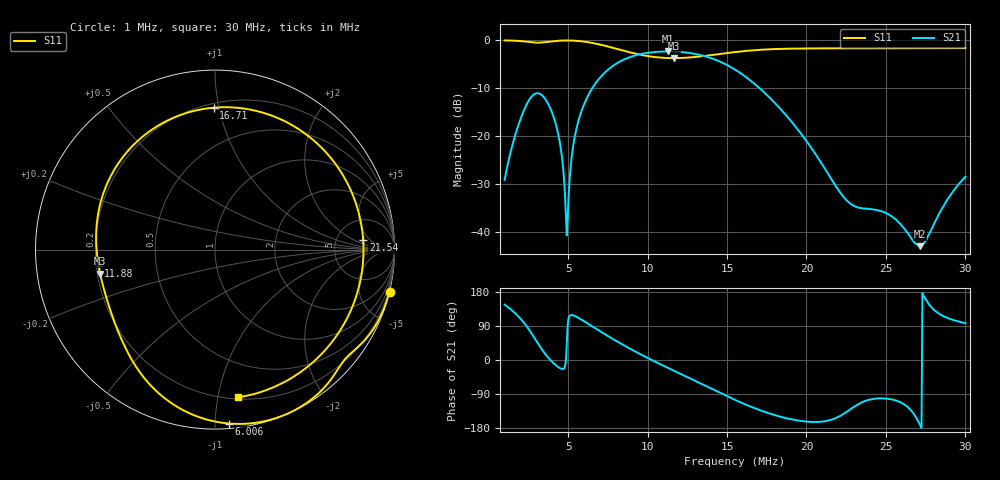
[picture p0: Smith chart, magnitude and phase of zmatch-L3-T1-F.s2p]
# HZ S RI R 50
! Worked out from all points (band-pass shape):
!   505 points, 1 MHz to 30 MHz, reference 50 ohm
!   highest |S21| = -2.30 dB at 11.3 MHz (marker M1); lowest = -43.0 dB at 27.12 MHz (marker M2)
!   |S21| within 3 dB of the highest: 7.824 MHz to 15.09 MHz (7.266 MHz wide, 63.4 % of centre)
!   lowest |S11| = -3.7 dB at 11.64 MHz (marker M3), VSWR 4.78, Z = 10.6 - j4.93 ohm
!   |S11| at or under -10 dB: nowhere
!   S12 and S22 are empty: the file has one direction only
!   S11 on the Smith chart (normalised r, x): 1 MHz: 0.00, -8.44; 6.006 MHz: 0.03, -1.08; 11.88 MHz: 0.21, -0.07; 16.71 MHz: 0.23, +0.96; 21.54 MHz: 10, +3; 30 MHz: 0.21, -1.15
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1000000  0.9723 -0.2336  -0.029 0.0195  0 0  0 0
2208340  0.8432 -0.4945  -0.0283 0.183  0 0  0 0
3244060  0.7047 -0.6362  0.2277 0.1555  0 0  0 0
4337320  0.5416 -0.831  0.1065 -0.0341  0 0  0 0
4912720  0.3995 -0.9166  0.00688 0.00614  0 0  0 0
5315500  0.2844 -0.9542  -0.0369 0.0697  0 0  0 0
5833360  0.1285 -0.9713  -0.0516 0.1745  0 0  0 0
6005980  0.0765 -0.9691  -0.0451 0.2117  0 0  0 0
8134960  -0.4049 -0.7019  0.3964 0.4322  0 0  0 0
1.066672e7  -0.5984 -0.2902  0.7537 -0.1124  0 0  0 0
1.129966e7  -0.6268 -0.1908  0.7153 -0.2783  0 0  0 0
1.16449e7  -0.6401 -0.1335  0.675 -0.3612  0 0  0 0
1.187506e7  -0.6477 -0.0935  0.6411 -0.4122  0 0  0 0
1.36588e7  -0.6341 0.275  0.2487 -0.6331  0 0  0 0
1.550008e7  -0.3475 0.6711  -0.1305 -0.4787  0 0  0 0
1.670842e7  -0.00746 0.7906  -0.2119 -0.2841  0 0  0 0
2.033344e7  0.7685 0.3023  -0.0711 -0.021  0 0  0 0
2.154178e7  0.8257 0.0515  -0.0334 -0.0136  0 0  0 0
2.292274e7  0.8025 -0.2055  -0.011 -0.0154  0 0  0 0
2.51668e7  0.6443 -0.5242  -0.00342 -0.0149  0 0  0 0
2.712316e7  0.4466 -0.7027  -0.00697 -0.0013  0 0  0 0
3.000016e7  0.1304 -0.8233  -0.00472 0.0374  0 0  0 0
